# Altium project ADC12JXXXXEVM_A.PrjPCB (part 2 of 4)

## Sheet ADC12JXXXXEVM_A_3_TRF3765.SchDoc: TRF3765
size 431 x 279 mm; Date: Not shown in title block; ApprovedBy: Not shown in title block; CheckedBy: Not shown in title block; Author: Not shown in title block; CompanyName: Not shown in title block; DrawnBy: Not shown in title block; Engineer: Not shown in title block; Organization: Not shown in title block; Address1: Not shown in title block; Address2: Not shown in title block; Address3: Not shown in title block; Address4: Not shown in title block; DocumentNumber: 3; Revision: Use project parameter SCH_Rev; SheetNumber: 3; SheetTotal: 7; PageSetup: Record=PageOptions|CenterHorizontal=True|CenterVertical=True|PrintScale=0.49|XCorrection=1.00|YCorrection=1.00|PrintKind=0|BorderSize=5000000|LeftOffset=0|BottomOffset=0|Orientation=2|PaperLength=1000|PaperWidth=1000|Scale=100|PaperSource=15|PrintQuality=600|MediaType=1|DitherType=10|PaperKind=11x17|PrintScaleMode=1

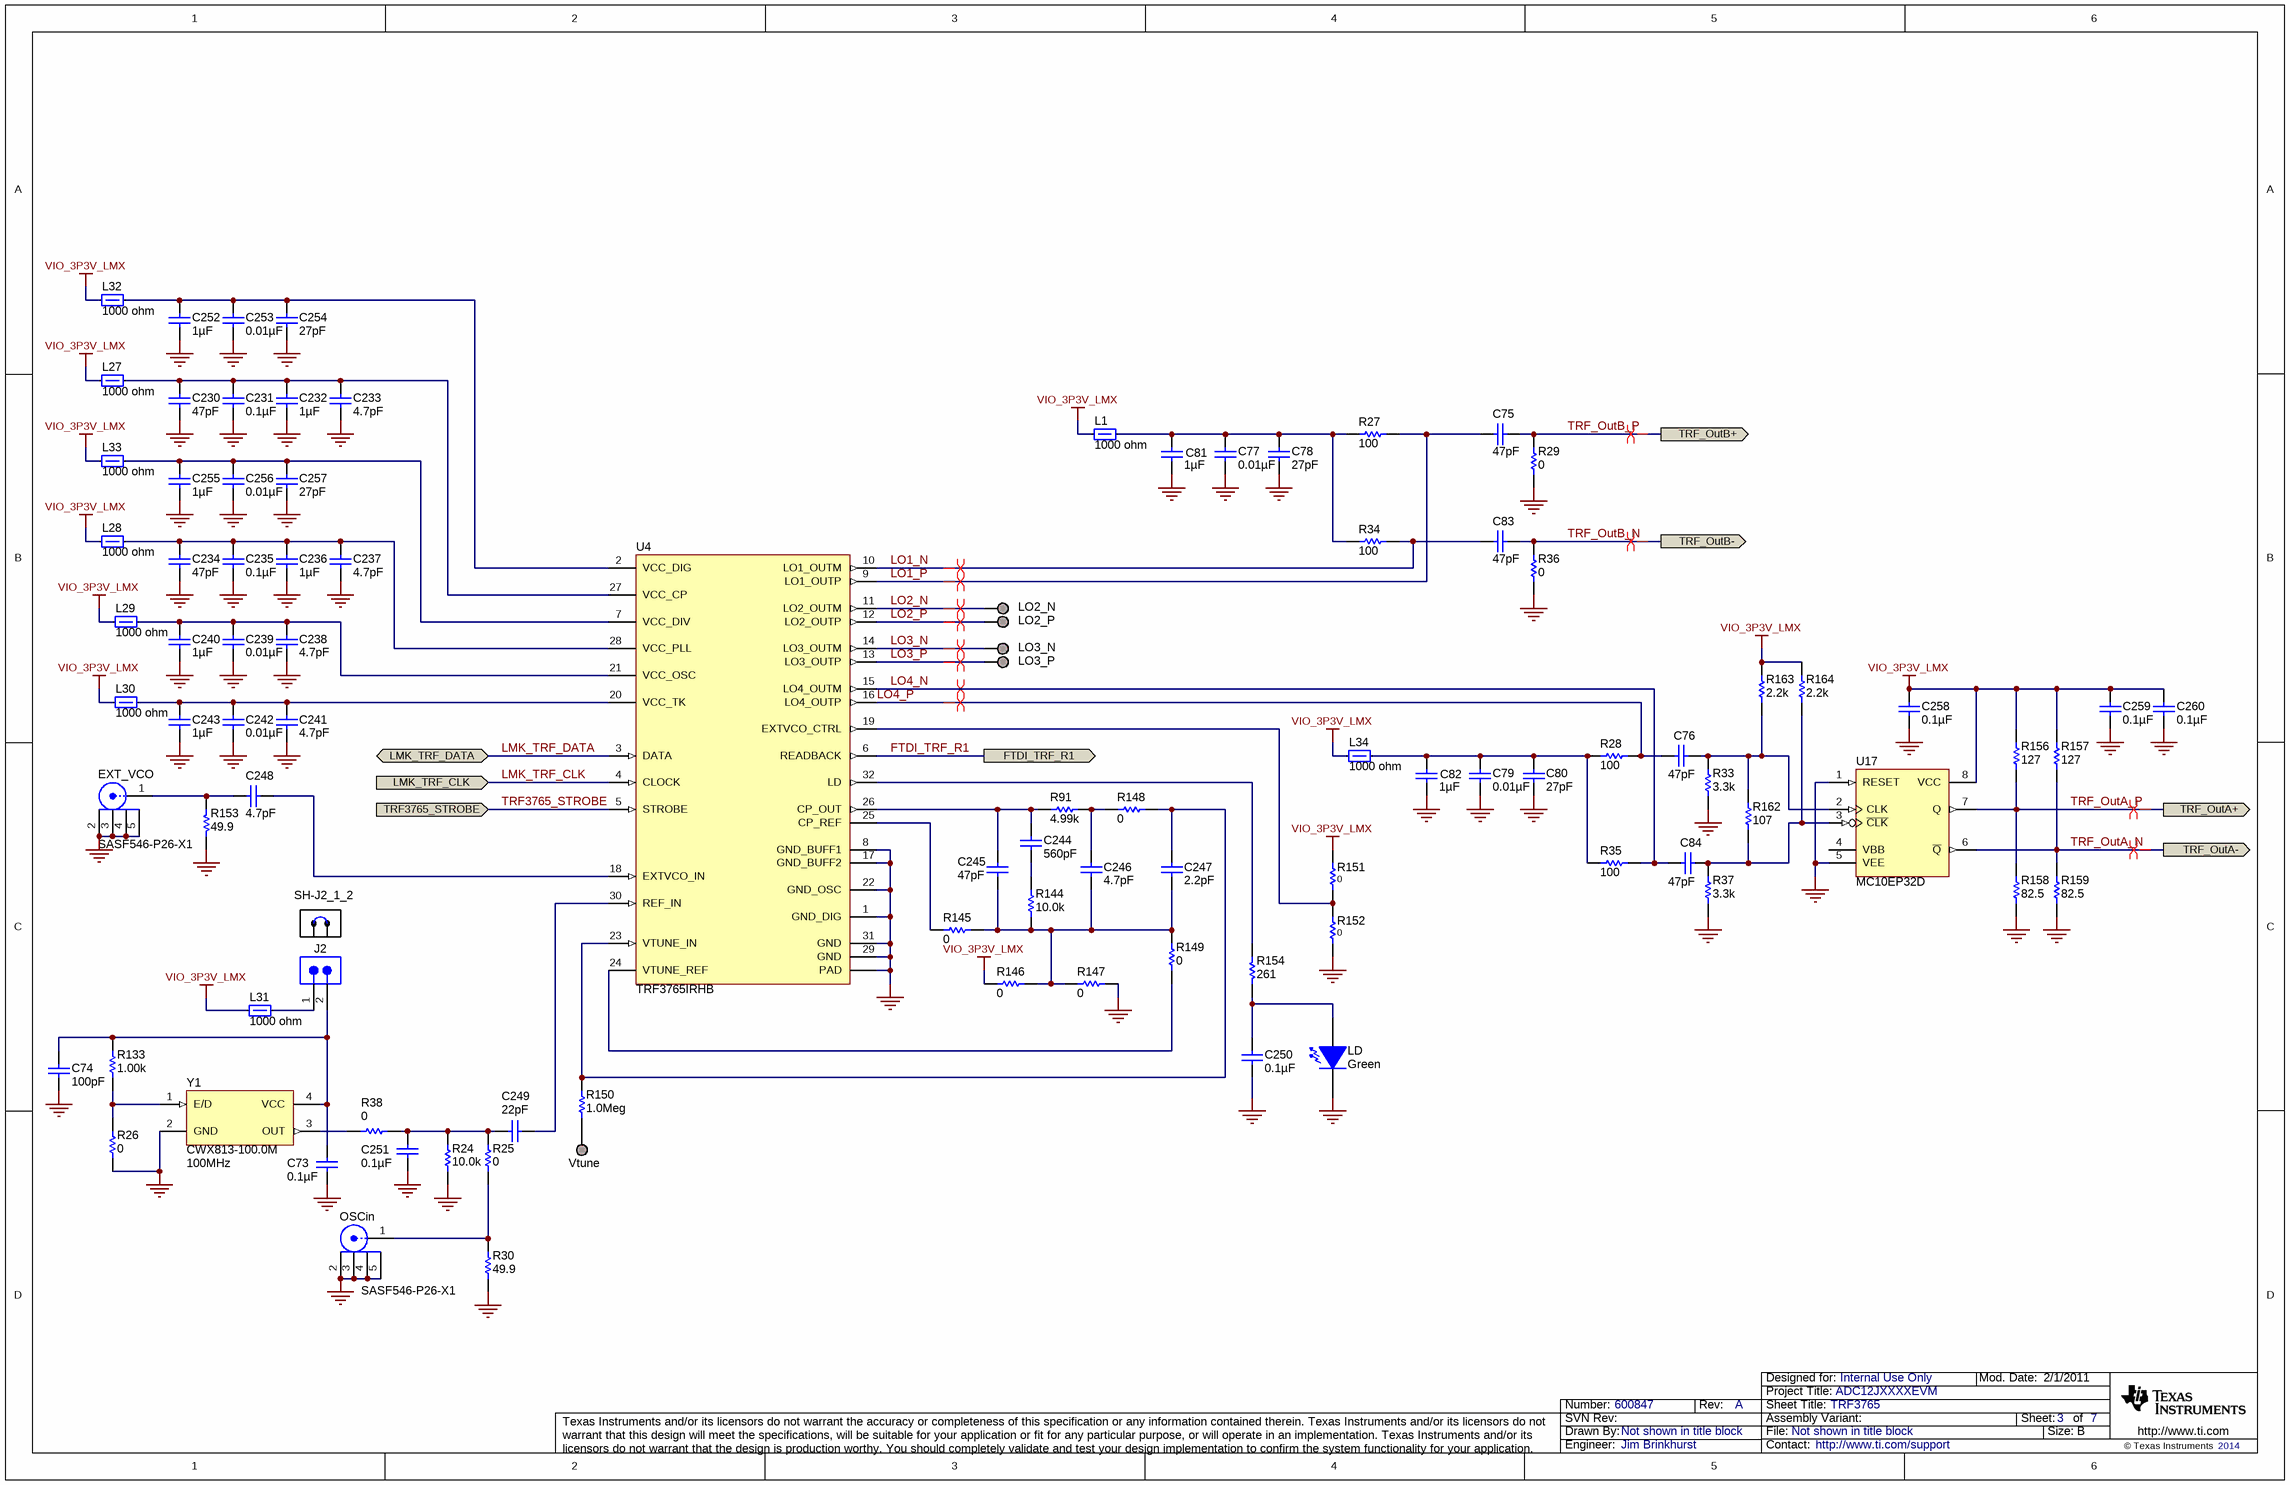
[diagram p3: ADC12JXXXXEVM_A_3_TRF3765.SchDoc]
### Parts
C73  ValueDisplayed: 0.1µF  [0402L]  (hidden comment: C1005X5R1A104K)
C74  ValueDisplayed: 100pF  [0402L]  (hidden comment: GRM1555C1E101JA01D)
C75  ValueDisplayed: 47pF  [0402L]  (hidden comment: GRM1555C1H470JA01D)
C76  ValueDisplayed: 47pF  [0402L]  (hidden comment: GRM1555C1H470JA01D)
C77  ValueDisplayed: 0.01µF  [0402L]  (hidden comment: GRM155R71E103KA01D)
C78  ValueDisplayed: 27pF  [0402L]  (hidden comment: GRM1555C1H270JA01D)
C79  ValueDisplayed: 0.01µF  [0402L]  (hidden comment: GRM155R71E103KA01D)
C80  ValueDisplayed: 27pF  [0402L]  (hidden comment: GRM1555C1H270JA01D)
C81  ValueDisplayed: 1µF  [0402L]  (hidden comment: C1005X5R0J105M)
C82  ValueDisplayed: 1µF  [0402L]  (hidden comment: C1005X5R0J105M)
C83  ValueDisplayed: 47pF  [0402L]  (hidden comment: GRM1555C1H470JA01D)
C84  ValueDisplayed: 47pF  [0402L]  (hidden comment: GRM1555C1H470JA01D)
C230  ValueDisplayed: 47pF  [0603L]  (hidden comment: GRM1885C1H470JA01D)
C231  ValueDisplayed: 0.1µF  [0402L]  (hidden comment: C1005X5R1A104K)
C232  ValueDisplayed: 1µF  [0402L]  (hidden comment: C1005X5R0J105M)
C233  ValueDisplayed: 4.7pF  [0402L]  (hidden comment: GRM1555C1H4R7CA01D)
C234  ValueDisplayed: 47pF  [0603L]  (hidden comment: GRM1885C1H470JA01D)
C235  ValueDisplayed: 0.1µF  [0402L]  (hidden comment: C1005X5R1A104K)
C236  ValueDisplayed: 1µF  [0402L]  (hidden comment: C1005X5R0J105M)
C237  ValueDisplayed: 4.7pF  [0402L]  (hidden comment: GRM1555C1H4R7CA01D)
C238  ValueDisplayed: 4.7pF  [0402L]  (hidden comment: GRM1555C1H4R7CA01D)
C239  ValueDisplayed: 0.01µF  [0402L]  (hidden comment: GRM155R71E103KA01D)
C240  ValueDisplayed: 1µF  [0402L]  (hidden comment: C1005X5R0J105M)
C241  ValueDisplayed: 4.7pF  [0402L]  (hidden comment: GRM1555C1H4R7CA01D)
C242  ValueDisplayed: 0.01µF  [0402L]  (hidden comment: GRM155R71E103KA01D)
C243  ValueDisplayed: 1µF  [0402L]  (hidden comment: C1005X5R0J105M)
C244  ValueDisplayed: 560pF  [0402L]  (hidden comment: GRM1555C1H561JA01D)
C245  ValueDisplayed: 47pF  [0402L]  (hidden comment: GRM1555C1H470JA01D)
C246  ValueDisplayed: 4.7pF  [0402L]  (hidden comment: GRM1555C1H4R7CA01D)
C247  ValueDisplayed: 2.2pF  [0402L]  (hidden comment: GRM1555C1H2R2CA01D)
C248  ValueDisplayed: 4.7pF  [0402L]  (hidden comment: GRM1555C1H4R7CA01D)
C249  ValueDisplayed: 22pF  [0402L]  (hidden comment: GRM1555C1H220JA01D)
C250  ValueDisplayed: 0.1µF  [0402L]  (hidden comment: C1005X5R1A104K)
C251  ValueDisplayed: 0.1µF  [0402L]  (hidden comment: C1005X5R1A104K)
C252  ValueDisplayed: 1µF  [0402L]  (hidden comment: C1005X5R0J105M)
C253  ValueDisplayed: 0.01µF  [0402L]  (hidden comment: GRM155R71E103KA01D)
C254  ValueDisplayed: 27pF  [0402L]  (hidden comment: GRM1555C1H270JA01D)
C255  ValueDisplayed: 1µF  [0402L]  (hidden comment: C1005X5R0J105M)
C256  ValueDisplayed: 0.01µF  [0402L]  (hidden comment: GRM155R71E103KA01D)
C257  ValueDisplayed: 27pF  [0402L]  (hidden comment: GRM1555C1H270JA01D)
C258  ValueDisplayed: 0.1µF  [0402L]  (hidden comment: C1005X5R1A104K)
C259  ValueDisplayed: 0.1µF  [0402L]  (hidden comment: C1005X5R1A104K)
C260  ValueDisplayed: 0.1µF  [0402L]  (hidden comment: C1005X5R1A104K)
EXT_VCO  SASF546-P26-X1  [CONN_LTI_SASF546-P26-X1]
J2  TSW-102-07-G-S  [TSW-102-07-G-S]  (value not drawn)
L1  value 1000 ohm  [0402L]  (hidden comment: BLM15HG102SN1D)
L27  value 1000 ohm  [0402L]  (hidden comment: BLM15HG102SN1D)
L28  value 1000 ohm  [0402L]  (hidden comment: BLM15HG102SN1D)
L29  value 1000 ohm  [0402L]  (hidden comment: BLM15HG102SN1D)
L30  value 1000 ohm  [0402L]  (hidden comment: BLM15HG102SN1D)
L31  value 1000 ohm  [0402L]  (hidden comment: BLM15HG102SN1D)
L32  value 1000 ohm  [0402L]  (hidden comment: BLM15HG102SN1D)
L33  value 1000 ohm  [0402L]  (hidden comment: BLM15HG102SN1D)
L34  value 1000 ohm  [0402L]  (hidden comment: BLM15HG102SN1D)
LD  value Green  [LED_LTST-C190]  (hidden comment: LTST-C190GKT)
LO2_N  TESTPOINT  [TESTPOINT]  (value not drawn)  (no BOM)
LO2_P  TESTPOINT  [TESTPOINT]  (value not drawn)  (no BOM)
LO3_N  TESTPOINT  [TESTPOINT]  (value not drawn)  (no BOM)
LO3_P  TESTPOINT  [TESTPOINT]  (value not drawn)  (no BOM)
OSCin  SASF546-P26-X1  [CONN_LTI_SASF546-P26-X1]
R24  value 10.0k  [0402L]  (hidden comment: CRCW040210K0FKED)
R25  value 0  [0402L]  (hidden comment: ERJ-2GE0R00X)
R26  value 0  [0402L]  (hidden comment: ERJ-2GE0R00X)
R27  value 100  [0402L]  (hidden comment: CRCW0402100RFKED)
R28  value 100  [0402L]  (hidden comment: CRCW0402100RFKED)
R29  value 0  [0402L]  (hidden comment: ERJ-2GE0R00X)
R30  value 49.9  [0402L]  (hidden comment: CRCW040249R9FKED)
R33  value 3.3k  [0402L]  (hidden comment: CRCW04023K30JNED)
R34  value 100  [0402L]  (hidden comment: CRCW0402100RFKED)
R35  value 100  [0402L]  (hidden comment: CRCW0402100RFKED)
R36  value 0  [0402L]  (hidden comment: ERJ-2GE0R00X)
R37  value 3.3k  [0402L]  (hidden comment: CRCW04023K30JNED)
R38  value 0  [0402L]  (hidden comment: ERJ-2GE0R00X)
R91  value 4.99k  [0402L]  (hidden comment: CRCW04024K99FKED)
R133  value 1.00k  [0402L]  (hidden comment: CRCW04021K00FKED)
R144  value 10.0k  [0402L]  (hidden comment: CRCW040210K0FKED)
R145  value 0  [0402L]  (hidden comment: ERJ-2GE0R00X)
R146  value 0  [0402L]  (hidden comment: ERJ-2GE0R00X)
R147  value 0  [0402L]  (hidden comment: ERJ-2GE0R00X)
R148  value 0  [0402L]  (hidden comment: ERJ-2GE0R00X)
R149  value 0  [0402L]  (hidden comment: ERJ-2GE0R00X)
R150  value 1.0Meg  [0402L]  (hidden comment: CRCW04021M00JNED)
R151  value 0  [0603L]  (hidden comment: CRCW06030000Z0EA)
R152  value 0  [0603L]  (hidden comment: CRCW06030000Z0EA)
R153  value 49.9  [0402L]  (hidden comment: CRCW040249R9FKED)
R154  value 261  [0402L]  (hidden comment: CRCW040215K0JNED)
R156  value 127  [0402L]  (hidden comment: CRCW0402127RFKED)
R157  value 127  [0402L]  (hidden comment: CRCW0402127RFKED)
R158  value 82.5  [0402L]  (hidden comment: CRCW040282R5FKED)
R159  value 82.5  [0402L]  (hidden comment: CRCW040282R5FKED)
R162  value 107  [0402L]  (hidden comment: CRCW0402107RFKED)
R163  value 2.2k  [0402L]  (hidden comment: CRCW04022K20JNED)
R164  value 2.2k  [0402L]  (hidden comment: CRCW04022K20JNED)
SH-J2_1_2  SNT-100-BK-G  [SNT-100-BK-G]  (value not drawn)
U4  TRF3765IRHB  [RHB0032E]
U17  MC10EP32D  [751-06_N]
Vtune  TESTPOINT  [TESTPOINT]  (value not drawn)  (no BOM)
Y1  CWX813-100.0M  Frequency: 100MHz  [OSC_CWX]

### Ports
FTDI_TRF_R1, LMK_TRF_CLK, LMK_TRF_DATA (bidir), TRF3765_STROBE, TRF_OutA+ (out), TRF_OutA- (out), TRF_OutB+, TRF_OutB-

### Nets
GND: C73.1 C74.1 C77.2 C78.2 C79.2 C80.2 C81.2 C82.2 C230.2 C231.1 C232.2 C233.2 C234.2 C235.1 C236.2 C237.2 C238.2 C239.2 C240.2 C241.2 C242.2 C243.2 C250.1 C251.1 C252.2 C253.2 C254.2 C255.2 C256.2 C257.2 C258.1 C259.1 C260.1 EXT_VCO.2 EXT_VCO.3 EXT_VCO.4 EXT_VCO.5 LD.2(K) OSCin.2 OSCin.3 OSCin.4 OSCin.5 R24.1 R26.1 R29.1 R30.1 R33.1 R36.1 R37.1 R147.2 R152.2 R153.1 R158.1 R159.1 U4.1(GND_DIG) U4.8(GND_BUFF1) U4.17(GND_BUFF2) U4.22(GND_OSC) U4.29(GND) U4.31(GND) U4.33(PAD) U17.1(RESET) U17.5(VEE) Y1.2(GND)
VIO_3P3V_LMX: C258.2 C259.2 C260.2 L1.1 L27.1 L28.1 L29.1 L30.1 L31.1 L32.1 L33.1 L34.1 R146.1 R151.1 R156.2 R157.2 R163.2 R164.2 U17.8(VCC)
FTDI_TRF_R1: U4.6(READBACK) ; port FTDI_TRF_R1
LMK_TRF_CLK: U4.4(CLOCK) ; port LMK_TRF_CLK
LMK_TRF_DATA: U4.3(DATA) ; port LMK_TRF_DATA
LO1_N: C83.1 R34.2 U4.10(LO1_OUTM)
LO1_P: C75.1 R27.2 U4.9(LO1_OUTP)
LO2_N: LO2_N.1 U4.11(LO2_OUTM)
LO2_P: LO2_P.1 U4.12(LO2_OUTP)
LO3_N: LO3_N.1 U4.14(LO3_OUTM)
LO3_P: LO3_P.1 U4.13(LO3_OUTP)
LO4_N: C84.1 R35.2 U4.15(LO4_OUTM)
LO4_P: C76.1 R28.2 U4.16(LO4_OUTP)
TRF3765_STROBE: U4.5(STROBE) ; port TRF3765_STROBE
TRF_OutA_N: R157.1 R159.2 U17.6(~{Q}) ; port TRF_OutA-
TRF_OutA_P: R156.1 R158.2 U17.7(Q) ; port TRF_OutA+
TRF_OutB_N: C83.2 R36.2 ; port TRF_OutB-
TRF_OutB_P: C75.2 R29.2 ; port TRF_OutB+
NetC73_2: C73.2 C74.2 J2.2 R133.2 Y1.4(VCC)
NetC76_2: C76.2 R33.2 R162.2 R163.1 U17.2(CLK)
NetC77_1: C77.1 C78.1 C81.1 L1.2 R27.1 R34.1
NetC79_1: C79.1 C80.1 C82.1 L34.2 R28.1 R35.1
NetC84_2: C84.2 R37.2 R162.1 R164.1 U17.3(~{CLK})
NetC230_1: C230.1 C231.2 C232.1 C233.1 L27.2 U4.27(VCC_CP)
NetC234_1: C234.1 C235.2 C236.1 C237.1 L28.2 U4.28(VCC_PLL)
NetC238_1: C238.1 C239.1 C240.1 L29.2 U4.21(VCC_OSC)
NetC241_1: C241.1 C242.1 C243.1 L30.2 U4.20(VCC_TK)
NetC244_1: C244.1 C245.1 R91.1 U4.26(CP_OUT)
NetC244_2: C244.2 R144.2
NetC245_2: C245.2 C246.2 C247.2 R144.1 R145.2 R146.2 R147.1 R149.1
NetC246_1: C246.1 R91.2 R148.1
NetC247_1: C247.1 R148.2 R150.1 U4.23(VTUNE_IN)
NetC248_1: C248.1 U4.18(EXTVCO_IN)
NetC248_2: C248.2 EXT_VCO.1 R153.2
NetC249_1: C249.1 U4.30(REF_IN)
NetC249_2: C249.2 C251.2 R24.2 R25.2 R38.1
NetC250_2: C250.2 LD.1(A) R154.1
NetC252_1: C252.1 C253.1 C254.1 L32.2 U4.2(VCC_DIG)
NetC255_1: C255.1 C256.1 C257.1 L33.2 U4.7(VCC_DIV)
NetJ2_1: J2.1 L31.2
NetOSCin_1: OSCin.1 R25.1 R30.2
NetR26_2: R26.2 R133.1 Y1.1(E/D)
NetR38_2: R38.2 Y1.3(OUT)
NetR145_1: R145.1 U4.25(CP_REF)
NetR149_2: R149.2 U4.24(VTUNE_REF)
NetR150_2: R150.2 Vtune.1
NetR151_2: R151.2 R152.1 U4.19(EXTVCO_CTRL)
NetR154_2: R154.2 U4.32(LD)

Not connected (* = marked no-connect by the designer): U17 4(VBB)

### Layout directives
differential pair: LO1_N, LO1_P, LO2_N, LO2_P, LO3_N, LO3_P, LO4_N, LO4_P, TRF_OutA_N, TRF_OutA_P, TRF_OutB_N, TRF_OutB_P

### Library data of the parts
C73 C231 C235 C250 C251 C258-C260 = C1005X5R1A104K: CAP, CERM, 0.1uF, 10V, +/-10%, X5R, 0402; Manufacturer: TDK; Polarized: N; CompType: Capacitor; U/M: EA; Cap_F: 0.0000001; Tolerance_%: 10; ESR_Ohm: 0.0186; Value1: 0.0186 ohm; TaMin_C: -55; TaMax_C: 85; Cap_Case: 0402
C74 = GRM1555C1E101JA01D: CAP, CERM, 100pF, 25V, +/-5%, C0G/NP0, 0402; Manufacturer: MuRata; Cap_Case: 0402; Polarized: N; TaMax_C: 125; TaMin_C: -55; Tolerance_%: 5; VDC_V: 25; Cap_F: 0.0000000001; CompType: Capacitor; U/M: EA
C75 C76 C83 C84 C245 = GRM1555C1H470JA01D: CAP, CERM, 47pF, 50V, +/-5%, C0G/NP0, 0402; Manufacturer: MuRata; Polarized: N; CompType: Capacitor; U/M: EA; Cap_F: 0.000000000047; Tolerance_%: 5; Value1: Unknown; VDC_V: 50; TaMin_C: -55; TaMax_C: 125; Cap_Case: 0402
C77 C79 C239 C242 C253 C256 = GRM155R71E103KA01D: CAP, CERM, 0.01uF, 25V, +/-10%, X7R, 0402; Manufacturer: MuRata; Polarized: N; CompType: Capacitor; U/M: EA; Cap_F: 0.00000001; Tolerance_%: 10; Value1: Unknown; VDC_V: 25; TaMin_C: -55; TaMax_C: 125; Cap_Case: 0402
C78 C80 C254 C257 = GRM1555C1H270JA01D: CAP, CERM, 27pF, 50V, +/-5%, C0G/NP0, 0402; Manufacturer: MuRata; Polarized: N; CompType: Capacitor; U/M: EA; Cap_F: 0.000000000027; Tolerance_%: 5; Value1: Unknown; VDC_V: 50; TaMin_C: -55; TaMax_C: 125; Cap_Case: 0402
C81 C82 C232 C236 C240 C243 C252 C255 = C1005X5R0J105M: CAP, CERM, 1uF, 6.3V, +/-20%, X5R, 0402; Manufacturer: TDK; Polarized: N; CompType: Capacitor; U/M: EA; Cap_F: 0.000001; Tolerance_%: 20; ESR_Ohm: 0.0079; Value1: 0.0079 ohm; VDC_V: 6.3; TaMin_C: -55; TaMax_C: 85; Cap_Case: 0402
C230 C234 = GRM1885C1H470JA01D: CAP, CERM, 47pF, 50V, +/-5%, C0G/NP0, 0603; Manufacturer: MuRata; Polarized: N; CompType: Capacitor; U/M: EA; Cap_F: 0.000000000047; Tolerance_%: 5; Value1: Unknown; VDC_V: 50; TaMin_C: -55; TaMax_C: 125; Cap_Case: 0603
C233 C237 C238 C241 C246 C248 = GRM1555C1H4R7CA01D: CAP, CERM, 4.7pF, 50V, +/-5%, C0G/NP0, 0402; Manufacturer: MuRata; Polarized: N; CompType: Capacitor; U/M: EA; Cap_F: 0.0000000000047; Tolerance_%: 5; Value1: Unknown; VDC_V: 50; TaMin_C: -55; TaMax_C: 125; Cap_Case: 0402
C244 = GRM1555C1H561JA01D: CAP, CERM, 560pF, 50V, +/-5%, C0G/NP0, 0402; Manufacturer: MuRata; Polarized: N; CompType: Capacitor; U/M: EA; Cap_F: 0.00000000056; Tolerance_%: 5; Value1: Unknown; VDC_V: 50; TaMin_C: -55; TaMax_C: 125; Cap_Case: 0402
C247 = GRM1555C1H2R2CA01D: CAP, CERM, 2.2pF, 50V, +/-5%, C0G/NP0, 0402; Manufacturer: MuRata; Polarized: N; CompType: Capacitor; U/M: EA; Cap_F: 0.0000000000022; Tolerance_%: 5; Value1: Unknown; VDC_V: 50; TaMin_C: -55; TaMax_C: 125; Cap_Case: 0402
C249 = GRM1555C1H220JA01D: CAP, CERM, 22pF, 50V, +/-5%, C0G/NP0, 0402; Manufacturer: MuRata; Polarized: N; CompType: Capacitor; U/M: EA; Cap_F: 0.000000000022; Tolerance_%: 5; Value1: Unknown; VDC_V: 50; TaMin_C: -55; TaMax_C: 125; Cap_Case: 0402
EXT_VCO OSCin = SASF546-P26-X1: Connector, SMA,Vertical, Thru hole w/SMT center pin; Manufacturer: Lighthorse Technologies; U/M: EA
J2 = TSW-102-07-G-S: Header, TH, 100mil, 2x1, Gold plated, 230 mil above insulator; Manufacturer: Samtec, Inc.; U/M: EA
L1 L27-L34 = BLM15HG102SN1D: 0.25A Ferrite Bead, 1000 ohm @ 100MHz, SMD; Manufacturer: MuRata; Imax_A: 0.25; Irms: 0.25A @ C rise; Isat: 0.25A @ % inductance drop; DCR_ohm: 1.1; Value1: 1.1 ohm; ZTyp@100MHz_Ohm: 1000; U/M: EA
LD = LTST-C190GKT: LED, Green, SMD; Manufacturer: Lite-On; Vf_V: 2.1; Value2: 2.1V; Io_A: 0.02; Power_TotalModule: 0.1; Value1: 0.1W; U/M: EA
LO2_N LO2_P LO3_N LO3_P Vtune = TESTPOINT: TEST POINT.  No entry in BOM.
R24 R144 = CRCW040210K0FKED: RES, 10.0k ohm, 1%, 0.063W, 0402; Manufacturer: Vishay-Dale; CompType: Resistor; Res_ohm: 10000; Value_Code: 10k0; Tolerance_%: 1; Power_W: 0.063; VDC_V: 50; TempCo: 100 ppm/C; EIA_Code: E96; U/M: EA
R25 R26 R29 R36 R38 R145-R149 = ERJ-2GE0R00X: RES, 0 ohm, 5%, 0.063W, 0402; Manufacturer: Panasonic; CompType: Resistor; Value_Code: 0000; Tolerance_%: 5; Power_W: 0.063; VDC_V: 50; TempCo: 600 ppm/C; EIA_Code: E24; U/M: EA
R27 R28 R34 R35 = CRCW0402100RFKED: RES, 100 ohm, 1%, 0.063W, 0402; Manufacturer: Vishay-Dale; CompType: Resistor; Value_Code: 100R; Tolerance_%: 1; Power_W: 0.063; VDC_V: 50; TempCo: 100 ppm/C; EIA_Code: E96; U/M: EA
R30 R153 = CRCW040249R9FKED: RES, 49.9 ohm, 1%, 0.063W, 0402; Manufacturer: Vishay-Dale; CompType: Resistor; Value_Code: 49R9; Tolerance_%: 1; Power_W: 0.063; VDC_V: 50; TempCo: 100 ppm/C; EIA_Code: E96; U/M: EA
R33 R37 = CRCW04023K30JNED: RES, 3.3k ohm, 5%, 0.063W, 0402; Manufacturer: Vishay-Dale; CompType: Resistor; Res_ohm: 3300; Value_Code: 3k30; Tolerance_%: 5; Power_W: 0.063; VDC_V: 50; TempCo: 200 ppm/C; EIA_Code: E24; U/M: EA
R91 = CRCW04024K99FKED: RES, 4.99k ohm, 1%, 0.063W, 0402; Manufacturer: Vishay-Dale; CompType: Resistor; Res_ohm: 4990; Value_Code: 4k99; Tolerance_%: 1; Power_W: 0.063; VDC_V: 50; TempCo: 100 ppm/C; EIA_Code: E96; U/M: EA
R133 = CRCW04021K00FKED: RES, 1.00k ohm, 1%, 0.063W, 0402; Manufacturer: Vishay-Dale; CompType: Resistor; Res_ohm: 1000; Value_Code: 1k00; Tolerance_%: 1; Power_W: 0.063; VDC_V: 50; TempCo: 100 ppm/C; EIA_Code: E96; U/M: EA
R150 = CRCW04021M00JNED: RES, 1.0Meg ohm, 5%, 0.063W, 0402; Manufacturer: Vishay-Dale; CompType: Resistor; Res_ohm: 1000000; Value_Code: 1M00; Tolerance_%: 5; Power_W: 0.063; VDC_V: 50; TempCo: 200 ppm/C; EIA_Code: E24; U/M: EA
R151 R152 = CRCW06030000Z0EA: RES, 0 ohm, 5%, 0.1W, 0603; Manufacturer: Vishay-Dale; CompType: Resistor; Tolerance_%: 5; VDC_V: 75; Power_W: 0.1; U/M: EA; Value_Code: 0000; EIA_Code: E24
R154 = CRCW040215K0JNED: RES, 15k ohm, 5%, 0.063W, 0402; Manufacturer: Vishay-Dale; CompType: Resistor; Res_ohm: 15000; Value_Code: 15k0; Tolerance_%: 5; Power_W: 0.063; VDC_V: 50; TempCo: 200 ppm/C; EIA_Code: E24; U/M: EA
R156 R157 = CRCW0402127RFKED: RES, 127 ohm, 1%, 0.063W, 0402; Manufacturer: Vishay-Dale; CompType: Resistor; Value_Code: 127R; Tolerance_%: 1; Power_W: 0.063; VDC_V: 50; TempCo: 100 ppm/C; EIA_Code: E96; U/M: EA
R158 R159 = CRCW040282R5FKED: RES, 82.5 ohm, 1%, 0.063W, 0402; Manufacturer: Vishay-Dale; CompType: Resistor; Value_Code: 82R5; Tolerance_%: 1; Power_W: 0.063; VDC_V: 50; TempCo: 100 ppm/C; EIA_Code: E96; U/M: EA
R162 = CRCW0402107RFKED: RES, 107 ohm, 1%, 0.063W, 0402; Manufacturer: Vishay-Dale; CompType: Resistor; Value_Code: 107R; Tolerance_%: 1; Power_W: 0.063; VDC_V: 50; TempCo: 100 ppm/C; EIA_Code: E96; U/M: EA
R163 R164 = CRCW04022K20JNED: RES, 2.2k ohm, 5%, 0.063W, 0402; Manufacturer: Vishay-Dale; CompType: Resistor; Res_ohm: 2200; Value_Code: 2k20; Tolerance_%: 5; Power_W: 0.063; VDC_V: 50; TempCo: 200 ppm/C; EIA_Code: E24; U/M: EA
SH-J2_1_2 = SNT-100-BK-G: Shunt, 100mil, Gold plated, Black; Manufacturer: Samtec, Inc.; Alternate Manufacturer: 3M; Alternate PartNumber: 969102-0000-DA; Value: 1x2; Note: You can "mate" this to a header by matching the designator.  i.e. use SH-J3 for header J3
U4 = TRF3765IRHB: Integer-N/Fractional-N PLL with Integrated VCO, RHB0032E; Alternate Manufacturer: None; Manufacturer: Texas Instruments; SymbolCreator: x0208326; CompType: IC; U/M: EA
U17 = MC10EP32D: Divide-by-2 Divider; Manufacturer: ON Semiconductor; PartNumber: MC10EP32DG
Y1 = CWX813-100.0M: OSC 100.0000MHZ 3.3V +-25PPM SMD; Manufacturer: Connor-Winfield; SymbolCreator: a0411947; CompType: Crystal; U/M: EA; TaMin_C: -20; TaMax_C: 70; Frequency Stability: ±25ppm

## Sheet ADC12JXXXXEVM_A_4_LMK04828.SchDoc
size 431 x 279 mm; Date: Not shown in title block; ApprovedBy: Not shown in title block; CheckedBy: Not shown in title block; Author: Not shown in title block; CompanyName: Not shown in title block; Engineer: Not shown in title block; Organization: Not shown in title block; Address1: Not shown in title block; Address2: Not shown in title block; Address3: Not shown in title block; Address4: Not shown in title block; DocumentNumber: 4; Revision: Use project parameter SCH_Rev; SheetNumber: 4; SheetTotal: 7; PageSetup: Record=PageOptions|CenterHorizontal=True|CenterVertical=True|PrintScale=0.47|XCorrection=1.00|YCorrection=1.00|PrintKind=0|BorderSize=5000000|LeftOffset=0|BottomOffset=0|Orientation=2|PaperLength=1000|PaperWidth=1000|Scale=100|PaperSource=7|PrintQuality=600|MediaType=1|DitherType=10|PaperKind=11" x 17"|PrintScaleMode=1

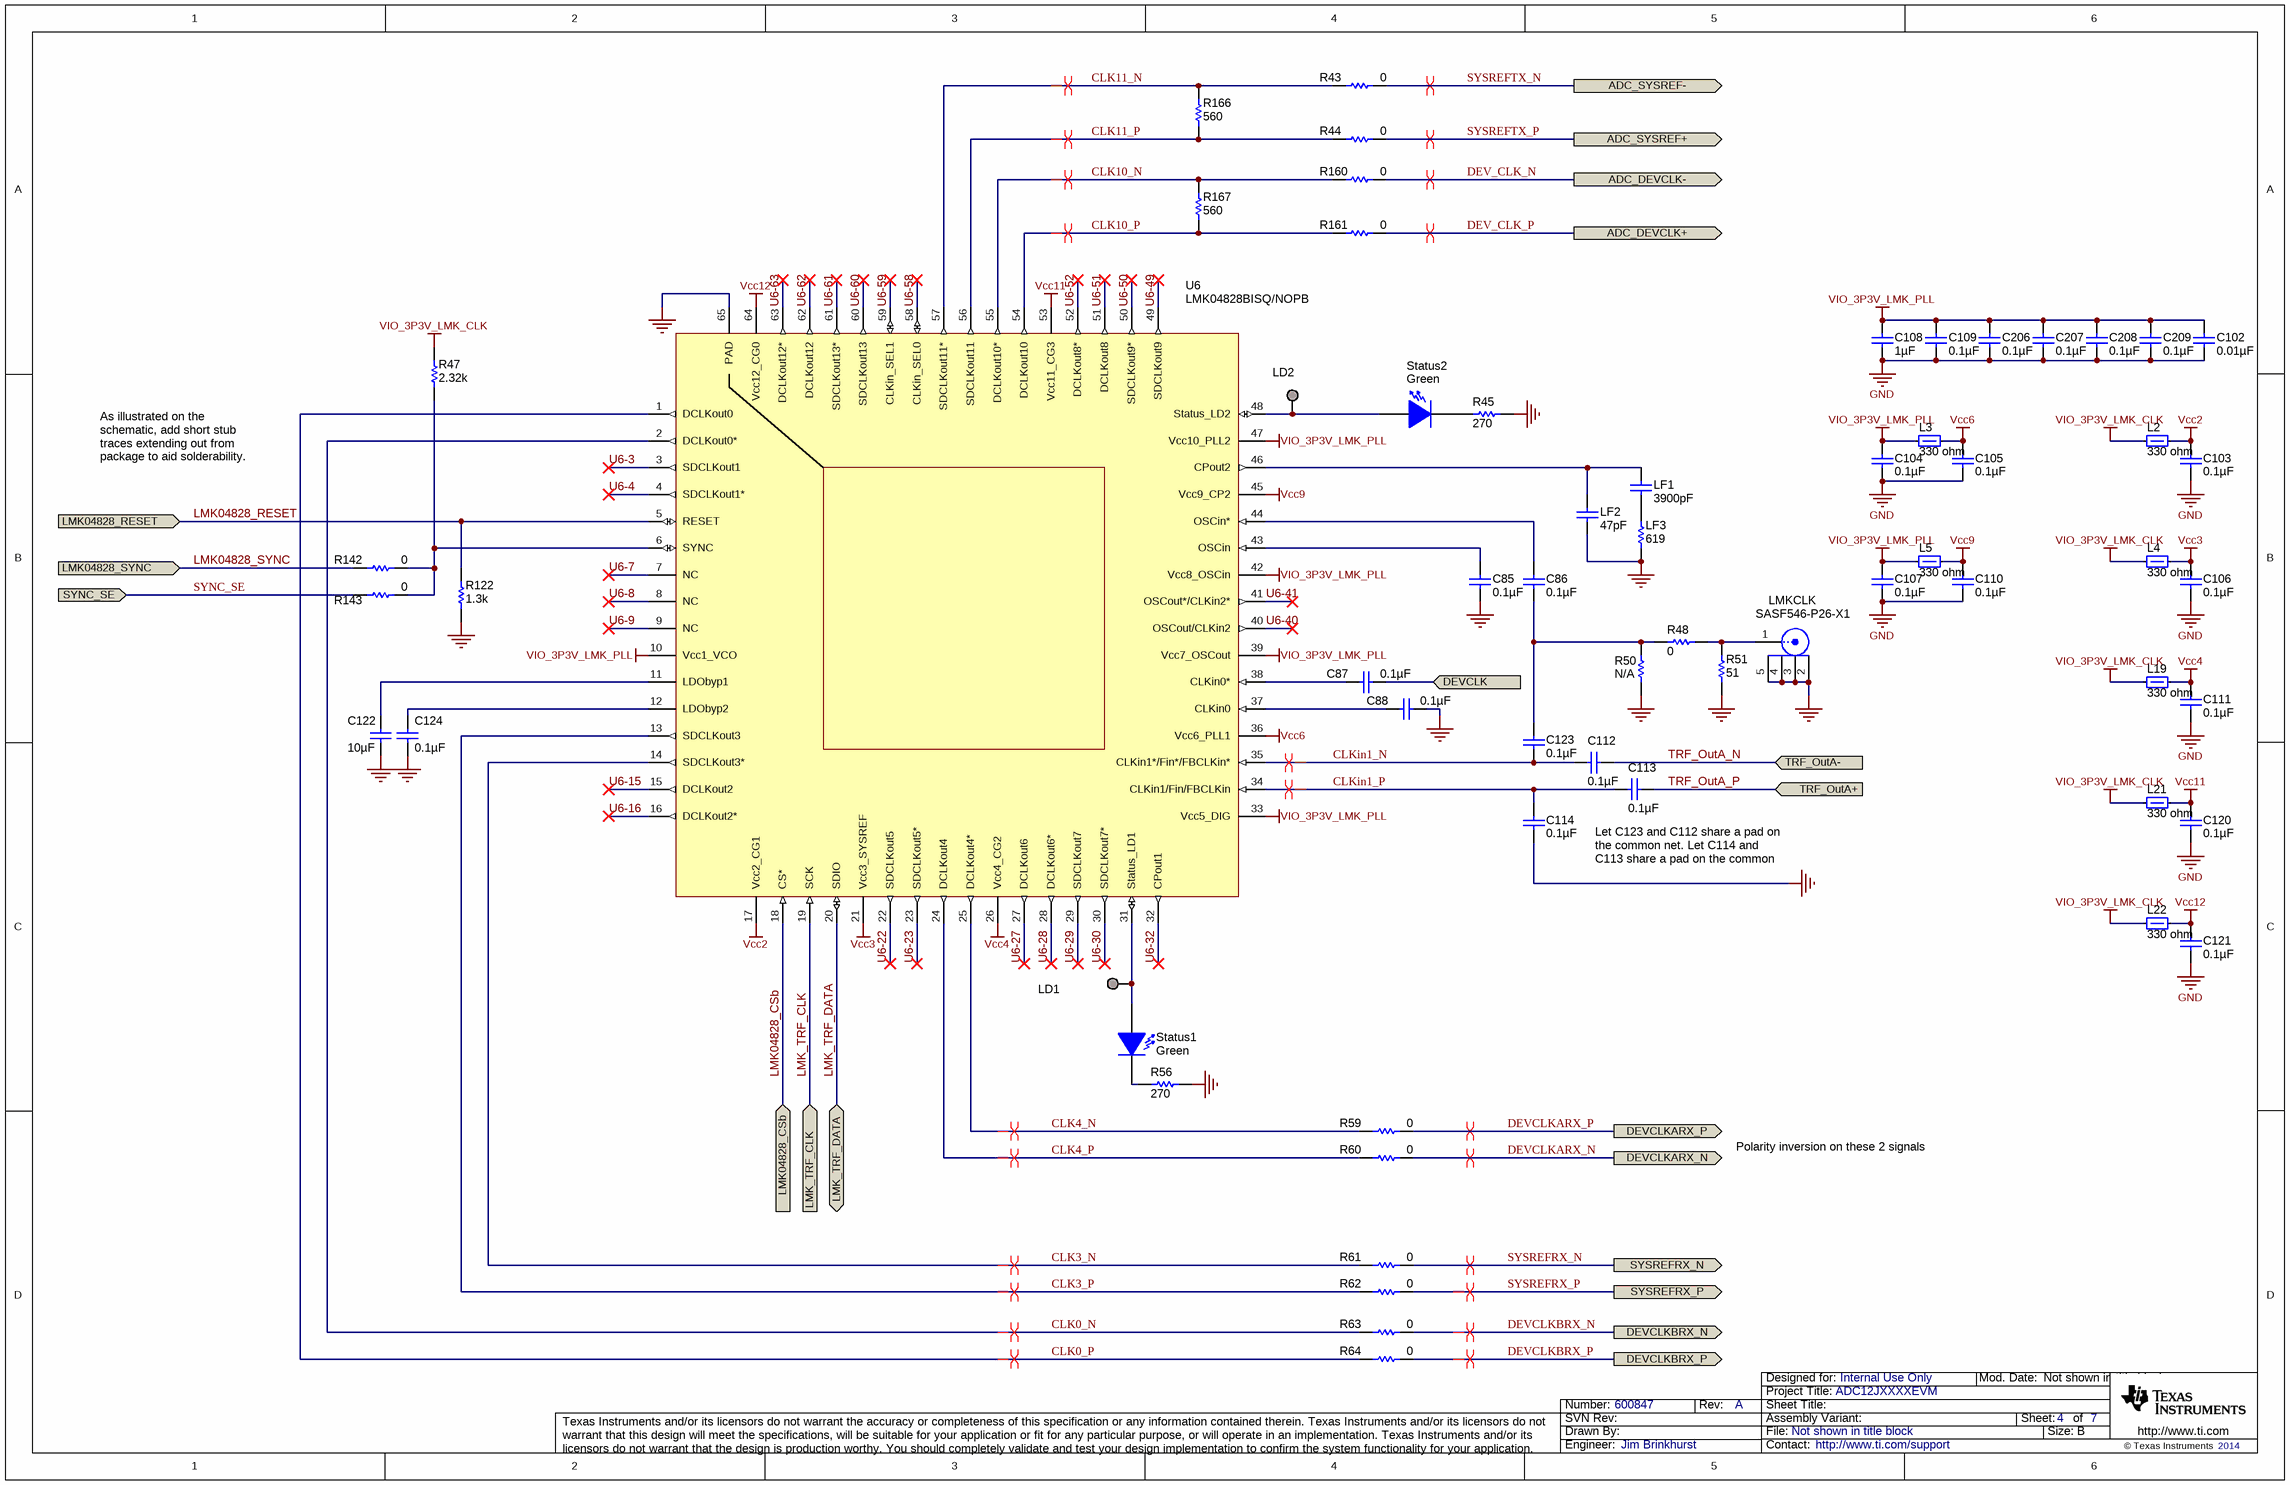
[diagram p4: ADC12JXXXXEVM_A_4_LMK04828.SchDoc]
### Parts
C85  ValueDisplayed: 0.1µF  [0402L]  (hidden comment: C1005X5R1A104K)
C86  ValueDisplayed: 0.1µF  [0402L]  (hidden comment: C1005X5R1A104K)
C87  ValueDisplayed: 0.1µF  [0402L]  (hidden comment: C1005X5R1A104K)
C88  ValueDisplayed: 0.1µF  [0402L]  (hidden comment: C1005X5R1A104K)
C102  ValueDisplayed: 0.01µF  [0402L]  (hidden comment: C1005X7R1C103K)
C103  ValueDisplayed: 0.1µF  [0402L]  (hidden comment: C1005X5R1A104K)
C104  ValueDisplayed: 0.1µF  [0402L]  (hidden comment: C1005X5R1A104K)
C105  ValueDisplayed: 0.1µF  [0402L]  (hidden comment: C1005X5R1A104K)
C106  ValueDisplayed: 0.1µF  [0402L]  (hidden comment: C1005X5R1A104K)
C107  ValueDisplayed: 0.1µF  [0402L]  (hidden comment: C1005X5R1A104K)
C108  ValueDisplayed: 1µF  [0603L]  (hidden comment: C1608X5R1C105K)
C109  ValueDisplayed: 0.1µF  [0402L]  (hidden comment: C1005X5R1A104K)
C110  ValueDisplayed: 0.1µF  [0402L]  (hidden comment: C1005X5R1A104K)
C111  ValueDisplayed: 0.1µF  [0402L]  (hidden comment: C1005X5R1A104K)
C112  ValueDisplayed: 0.1µF  [0402L]  (hidden comment: C1005X5R1A104K)
C113  ValueDisplayed: 0.1µF  [0402L]  (hidden comment: C1005X5R1A104K)
C114  ValueDisplayed: 0.1µF  [0402L]  (hidden comment: C1005X5R1A104K)
C120  ValueDisplayed: 0.1µF  [0402L]  (hidden comment: C1005X5R1A104K)
C121  ValueDisplayed: 0.1µF  [0402L]  (hidden comment: C1005X5R1A104K)
C122  ValueDisplayed: 10µF  [0805L]  (hidden comment: C0805C106K8PACTU)
C123  ValueDisplayed: 0.1µF  [0402L]  (hidden comment: C1005X5R1A104K)
C124  ValueDisplayed: 0.1µF  [0402L]  (hidden comment: C1005X5R1A104K)
C206  ValueDisplayed: 0.1µF  [0402L]  (hidden comment: C1005X5R1A104K)
C207  ValueDisplayed: 0.1µF  [0402L]  (hidden comment: C1005X5R1A104K)
C208  ValueDisplayed: 0.1µF  [0402L]  (hidden comment: C1005X5R1A104K)
C209  ValueDisplayed: 0.1µF  [0402L]  (hidden comment: C1005X5R1A104K)
L2  value 330 ohm  [0603]  (hidden comment: BLM18SG331TN1D)
L3  value 330 ohm  [0603]  (hidden comment: BLM18SG331TN1D)
L4  value 330 ohm  [0603]  (hidden comment: BLM18SG331TN1D)
L5  value 330 ohm  [0603]  (hidden comment: BLM18SG331TN1D)
L19  value 330 ohm  [0603]  (hidden comment: BLM18SG331TN1D)
L21  value 330 ohm  [0603]  (hidden comment: BLM18SG331TN1D)
L22  value 330 ohm  [0603]  (hidden comment: BLM18SG331TN1D)
LD1  TESTPOINT  [TESTPOINT]  (value not drawn)  (no BOM)
LD2  TESTPOINT  [TESTPOINT]  (value not drawn)  (no BOM)
LF1  ValueDisplayed: 3900pF  [0603L]  (hidden comment: C1608C0G1E392J)
LF2  ValueDisplayed: 47pF  [0603L]  (hidden comment: 06035A470JAT2A)
LF3  value 619  [0603L]  (hidden comment: RC0603FR-07619RL)
LMKCLK  SASF546-P26-X1  [CONN_LTI_SASF546-P26-X1]
R43  value 0  [0402L]  (hidden comment: CRCW04020000Z0ED)
R44  value 0  [0402L]  (hidden comment: CRCW04020000Z0ED)
R45  value 270  [0603L]  (hidden comment: CRCW0603270RJNEA)
R47  value 2.32k  [0603L]  (hidden comment: RC0603FR-072K32L)
R48  value 0  [0402L]  (hidden comment: CRCW04020000Z0ED)
R50  Used in BOM report  [0402L]  (value not drawn)
R51  value 51  [0402L]  (hidden comment: CRCW040251R0JNED)
R56  value 270  [0603L]  (hidden comment: CRCW0603270RJNEA)
R59  value 0  [0402L]  (hidden comment: CRCW04020000Z0ED)
R60  value 0  [0402L]  (hidden comment: CRCW04020000Z0ED)
R61  value 0  [0402L]  (hidden comment: CRCW04020000Z0ED)
R62  value 0  [0402L]  (hidden comment: CRCW04020000Z0ED)
R63  value 0  [0402L]  (hidden comment: CRCW04020000Z0ED)
R64  value 0  [0402L]  (hidden comment: CRCW04020000Z0ED)
R122  value 1.3k  [0603L]  (hidden comment: RC0603JR-071K3L)
R142  value 0  [0603L]  (hidden comment: ERJ-3GEY0R00V)
R143  value 0  [0603L]  (hidden comment: ERJ-3GEY0R00V)
R160  value 0  [0402L]  (hidden comment: CRCW04020000Z0ED)
R161  value 0  [0402L]  (hidden comment: CRCW04020000Z0ED)
R166  ValueDisplayed: 560  [0402L]  (hidden comment: CRCW0402560RJNED)
R167  ValueDisplayed: 560  [0402L]  (hidden comment: CRCW0402560RJNED)
Status1  value Green  [LED_LTST-C190]  (hidden comment: LTST-C190GKT)
Status2  value Green  [LED_LTST-C190]  (hidden comment: LTST-C190GKT)
U6  LMK04828BISQ/NOPB  [NKD0064A]

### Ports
ADC_DEVCLK+ (out), ADC_DEVCLK- (out), ADC_SYSREF+ (out), ADC_SYSREF- (out), DEVCLK (in), DEVCLKARX_N (out), DEVCLKARX_P (out), DEVCLKBRX_N (out), DEVCLKBRX_P (out), LMK04828_CSb (in), LMK04828_RESET (in), LMK04828_SYNC (in), LMK_TRF_CLK (in), LMK_TRF_DATA (bidir), SYNC_SE (in), SYSREFRX_N (out), SYSREFRX_P (out), TRF_OutA+ (in), TRF_OutA- (in)

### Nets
GND: C85.1 C88.2 C102.2 C103.2 C104.2 C105.2 C106.2 C107.2 C108.2 C109.2 C110.2 C111.2 C114.1 C120.2 C121.2 C122.2 C124.2 C206.2 C207.2 C208.2 C209.2 LF2.2 LF3.1 LMKCLK.2 LMKCLK.3 LMKCLK.4 LMKCLK.5 R45.1 R50.2 R51.1 R56.1 R122.1 U6.65(PAD)
Vcc2: C103.1 L2.2 U6.17(Vcc2_CG1)
Vcc3: C106.1 L4.2 U6.21(Vcc3_SYSREF)
Vcc4: C111.1 L19.2 U6.26(Vcc4_CG2)
Vcc6: C105.1 L3.2 U6.36(Vcc6_PLL1)
Vcc9: C110.1 L5.2 U6.45(Vcc9_CP2)
Vcc11: C120.1 L21.2 U6.53(Vcc11_CG3)
Vcc12: C121.1 L22.2 U6.64(Vcc12_CG0)
VIO_3P3V_LMK_CLK: L2.1 L4.1 L19.1 L21.1 L22.1 R47.2
VIO_3P3V_LMK_PLL: C102.1 C104.1 C107.1 C108.1 C109.1 C206.1 C207.1 C208.1 C209.1 L3.1 L5.1 U6.10(Vcc1_VCO) U6.33(Vcc5_DIG) U6.39(Vcc7_OSCout) U6.42(Vcc8_OSCin) U6.47(Vcc10_PLL2)
CLK0_N: R63.1 U6.2(DCLKout0*)
CLK0_P: R64.1 U6.1(DCLKout0)
CLK3_N: R61.1 U6.14(SDCLKout3*)
CLK3_P: R62.1 U6.13(SDCLKout3)
CLK4_N: R59.1 U6.25(DCLKout4*)
CLK4_P: R60.1 U6.24(DCLKout4)
CLK10_N: R160.1 R167.2 U6.55(DCLKout10*)
CLK10_P: R161.1 R167.1 U6.54(DCLKout10)
CLK11_N: R43.1 R166.2 U6.57(SDCLKout11*)
CLK11_P: R44.1 R166.1 U6.56(SDCLKout11)
CLKin1_N: C112.1 C123.1 U6.35(CLKin1*/Fin*/FBCLKin*)
CLKin1_P: C113.1 C114.2 U6.34(CLKin1/Fin/FBCLKin)
DEV_CLK_N: R160.2 ; port ADC_DEVCLK-
DEV_CLK_P: R161.2 ; port ADC_DEVCLK+
DEVCLKARX_N: R60.2 ; port DEVCLKARX_N
DEVCLKARX_P: R59.2 ; port DEVCLKARX_P
DEVCLKBRX_N: R63.2 ; port DEVCLKBRX_N
DEVCLKBRX_P: R64.2 ; port DEVCLKBRX_P
LMK04828_CSb: U6.18(CS*) ; port LMK04828_CSb
LMK04828_RESET: R122.2 U6.5(RESET) ; port LMK04828_RESET
LMK04828_SYNC: R142.1 ; port LMK04828_SYNC
LMK_TRF_CLK: U6.19(SCK) ; port LMK_TRF_CLK
LMK_TRF_DATA: U6.20(SDIO) ; port LMK_TRF_DATA
SYNC_SE: R143.1 ; port SYNC_SE
SYSREFRX_N: R61.2 ; port SYSREFRX_N
SYSREFRX_P: R62.2 ; port SYSREFRX_P
SYSREFTX_N: R43.2 ; port ADC_SYSREF-
SYSREFTX_P: R44.2 ; port ADC_SYSREF+
TRF_OutA_N: C112.2 ; port TRF_OutA-
TRF_OutA_P: C113.2 ; port TRF_OutA+
U6-3: U6.3(SDCLKout1)
U6-4: U6.4(SDCLKout1*)
U6-7: U6.7(NC)
U6-8: U6.8(NC)
U6-9: U6.9(NC)
U6-15: U6.15(DCLKout2)
U6-16: U6.16(DCLKout2*)
U6-22: U6.22(SDCLKout5)
U6-23: U6.23(SDCLKout5*)
U6-27: U6.27(DCLKout6)
U6-28: U6.28(DCLKout6*)
U6-29: U6.29(SDCLKout7)
U6-30: U6.30(SDCLKout7*)
U6-32: U6.32(CPout1)
U6-40: U6.40(OSCout/CLKin2)
U6-41: U6.41(OSCout*/CLKin2*)
U6-49: U6.49(SDCLKout9)
U6-50: U6.50(SDCLKout9*)
U6-51: U6.51(DCLKout8)
U6-52: U6.52(DCLKout8*)
U6-58: U6.58(CLKin_SEL0)
U6-59: U6.59(CLKin_SEL1)
U6-60: U6.60(SDCLKout13)
U6-61: U6.61(SDCLKout13*)
U6-62: U6.62(DCLKout12)
U6-63: U6.63(DCLKout12*)
NetC85_2: C85.2 U6.43(OSCin)
NetC86_1: C86.1 C123.2 R48.1 R50.1
NetC86_2: C86.2 U6.44(OSCin*)
NetC87_1: C87.1 U6.38(CLKin0*)
NetC87_2: C87.2 ; port DEVCLK
NetC88_1: C88.1 U6.37(CLKin0)
NetC122_1: C122.1 U6.11(LDObyp1)
NetC124_1: C124.1 U6.12(LDObyp2)
NetLD1_1: LD1.1 Status1.1(A) U6.31(Status_LD1)
NetLD2_1: LD2.1 Status2.1(A) U6.48(Status_LD2)
NetLF1_1: LF1.1 LF2.1 U6.46(CPout2)
NetLF1_2: LF1.2 LF3.2
NetLMKCLK_1: LMKCLK.1 R48.2 R51.2
NetR45_2: R45.2 Status2.2(K)
NetR47_1: R47.1 R142.2 R143.2 U6.6(SYNC)
NetR56_2: R56.2 Status1.2(K)

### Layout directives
differential pair: CLK0_N, CLK0_P, CLK3_N, CLK3_P, CLK4_N, CLK4_P, CLK10_N, CLK10_P, CLK11_N, CLK11_P, CLKin1_N, CLKin1_P, DEV_CLK_N, DEV_CLK_P, DEVCLKARX_N, DEVCLKARX_P, DEVCLKBRX_N, DEVCLKBRX_P, SYSREFRX_N, SYSREFRX_P, SYSREFTX_N, SYSREFTX_P

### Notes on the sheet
- As illustrated on the schematic, add short stub traces extending out from package to aid solderability.
- (near C113) Let C123 and C112 share a pad on the common net. Let C114 and C113 share a pad on the common net.
- Polarity inversion on these 2 signals

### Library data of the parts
C85-C88 C103-C107 C109-C114 C120 C121 C123 C124 C206-C209 = C1005X5R1A104K: as C73 on sheet ADC12JXXXXEVM_A_3_TRF3765
C102 = C1005X7R1C103K: CAP, CERM, 0.01uF, 16V, +/-10%, X7R, 0402; Manufacturer: TDK; Polarized: N; CompType: Capacitor; U/M: EA; Cap_F: 0.00000001; Tolerance_%: 10; ESR_Ohm: 0.0623; Value1: 0.0623 ohm; VDC_V: 16; TaMin_C: -55; TaMax_C: 125; Cap_Case: 0402
C108 = C1608X5R1C105K: CAP, CERM, 1uF, 16V, +/-10%, X5R, 0603; Manufacturer: TDK; Polarized: N; CompType: Capacitor; U/M: EA; Cap_F: 0.000001; Tolerance_%: 10; ESR_Ohm: 0.0057; Value1: 0.0057 ohm; VDC_V: 16; TaMin_C: -55; TaMax_C: 85; Cap_Case: 0603
C122 = C0805C106K8PACTU: CAP, CERM, 10uF, 10V, +/-10%, X5R, 0805; Manufacturer: Kemet; Cap_Case: 0805; ESR_Ohm: 0.003; IRMS_A: 11.43; Polarized: N; TaMax_C: 85; TaMin_C: -55; Tolerance_%: 10; Cap_F: 10.0E-6; CompType: Capacitor; Value1: 0.003 ohm
L2-L5 L19 L21 L22 = BLM18SG331TN1D: 1.5A Ferrite Bead, 330 ohm @ 100MHz, SMD; Manufacturer: MuRata; Imax_A: 1.5; DCR_ohm: 0.07; Value1: 0.07 ohm; ZTyp@100MHz_Ohm: 330; U/M: EA
LD1 LD2 = TESTPOINT: TEST POINT.  No entry in BOM.
LF1 = C1608C0G1E392J: CAP, CERM, 3900pF, 25V, +/-5%, C0G/NP0, 0603; Manufacturer: TDK; Polarized: N; CompType: Capacitor; U/M: EA; Cap_F: 0.0000000039; Tolerance_%: 5; VDC_V: 25; TaMin_C: -55; TaMax_C: 125; Cap_Case: 0603
LF2 = 06035A470JAT2A: CAP, CERM, 47pF, 50V, +/-5%, C0G/NP0, 0603; Manufacturer: AVX; Polarized: N; CompType: Capacitor; U/M: EA; Cap_F: 0.000000000047; Tolerance_%: 5; ESR_Ohm: 0.174; Value1: 0.174 ohm; VDC_V: 50; TaMin_C: -55; TaMax_C: 125; Cap_Case: 0603
LF3 = RC0603FR-07619RL: RES, 619 ohm, 1%, 0.1W, 0603; Manufacturer: Yageo America; Alternate Manufacturer: Any; Alternate PartNumber: Equivalent; CompType: Resistor; Value_Code: 619R; Tolerance_%: 1; Power_W: 0.1; VDC_V: 150; TempCo: 200 ppm/C; EIA_Code: E96; U/M: EA
LMKCLK = SASF546-P26-X1: as EXT_VCO on sheet ADC12JXXXXEVM_A_3_TRF3765
R43 R44 R59-R64 R160 R161 = CRCW04020000Z0ED: RES, 0 ohm, 5%, 0.063W, 0402; Manufacturer: Vishay-Dale; CompType: Resistor; Value_Code: 0000; Tolerance_%: 5; Power_W: 0.063; VDC_V: 50; TempCo: 200 ppm/C; EIA_Code: E24; U/M: EA
R45 R56 = CRCW0603270RJNEA: RES, 270 ohm, 5%, 0.1W, 0603; Manufacturer: Vishay-Dale; Alternate Manufacturer: Any; Alternate PartNumber: Equivalent; CompType: Resistor; Value_Code: 270R; Tolerance_%: 5; Power_W: 0.1; VDC_V: 75; TempCo: 200 ppm/C; EIA_Code: E24; U/M: EA
R47 = RC0603FR-072K32L: RES, 2.32k ohm, 1%, 0.1W, 0603; Manufacturer: Yageo America; CompType: Resistor; Res_ohm: 2320; Value_Code: 2k32; Tolerance_%: 1; Power_W: 0.1; VDC_V: 150; TempCo: 200 ppm/C; EIA_Code: E96; U/M: EA
R48 = CRCW04020000Z0ED: RES, 0 ohm, 5%, 0.063W, 0402; Manufacturer: Vishay-Dale; Alternate Manufacturer: Any; Alternate PartNumber: Equivalent; CompType: Resistor; Value_Code: 0000; Tolerance_%: 5; Power_W: 0.063; VDC_V: 50; TempCo: 200 ppm/C; EIA_Code: E24; U/M: EA
R50 = Resistor: RES, xxx ohm, x%, xW, [PackageReference]; U/M: EA
R51 = CRCW040251R0JNED: RES, 51 ohm, 5%, 0.063W, 0402; Manufacturer: Vishay-Dale; Alternate Manufacturer: Any; Alternate PartNumber: Equivalent; CompType: Resistor; Value_Code: 51R0; Tolerance_%: 5; Power_W: 0.063; VDC_V: 50; TempCo: 200 ppm/C; EIA_Code: E24; U/M: EA
R122 = RC0603JR-071K3L: RES, 1.3k ohm, 5%, 0.1W, 0603; Manufacturer: Yageo America; CompType: Resistor; Res_ohm: 1300; Value_Code: 1k30; Tolerance_%: 5; Power_W: 0.1; VDC_V: 50; TempCo: 100 ppm/C; EIA_Code: E24; U/M: EA
R142 R143 = ERJ-3GEY0R00V: RES, 0 ohm, 5%, 0.1W, 0603; Manufacturer: Panasonic; CompType: Resistor; Value_Code: 0000; Tolerance_%: 5; Power_W: 0.1; VDC_V: 50; TempCo: 600 ppm/C; EIA_Code: E24; U/M: EA
R166 R167 = CRCW0402560RJNED: RES, 560, 5%, 0.063 W, 0402; Manufacturer: Vishay-Dale; CompType: Resistor; Value: 560; Value_Code: 560R; Tolerance_%: 5; Power_W: 0.063; Value2: 0.063W; VDC_V: 50; TempCo: 200 ppm/C; EIA_Code: E24; U/M: EA
Status1 Status2 = LTST-C190GKT: as LD on sheet ADC12JXXXXEVM_A_3_TRF3765
U6 = LMK04828BISQ/NOPB: Low-Noise Clock Jitter Cleaner with Dual Loop PLLs, NKD0064A; Alternate Manufacturer: None; Manufacturer: Texas Instruments; SymbolCreator: a0411947/a0412235; CompType: IC; U/M: EA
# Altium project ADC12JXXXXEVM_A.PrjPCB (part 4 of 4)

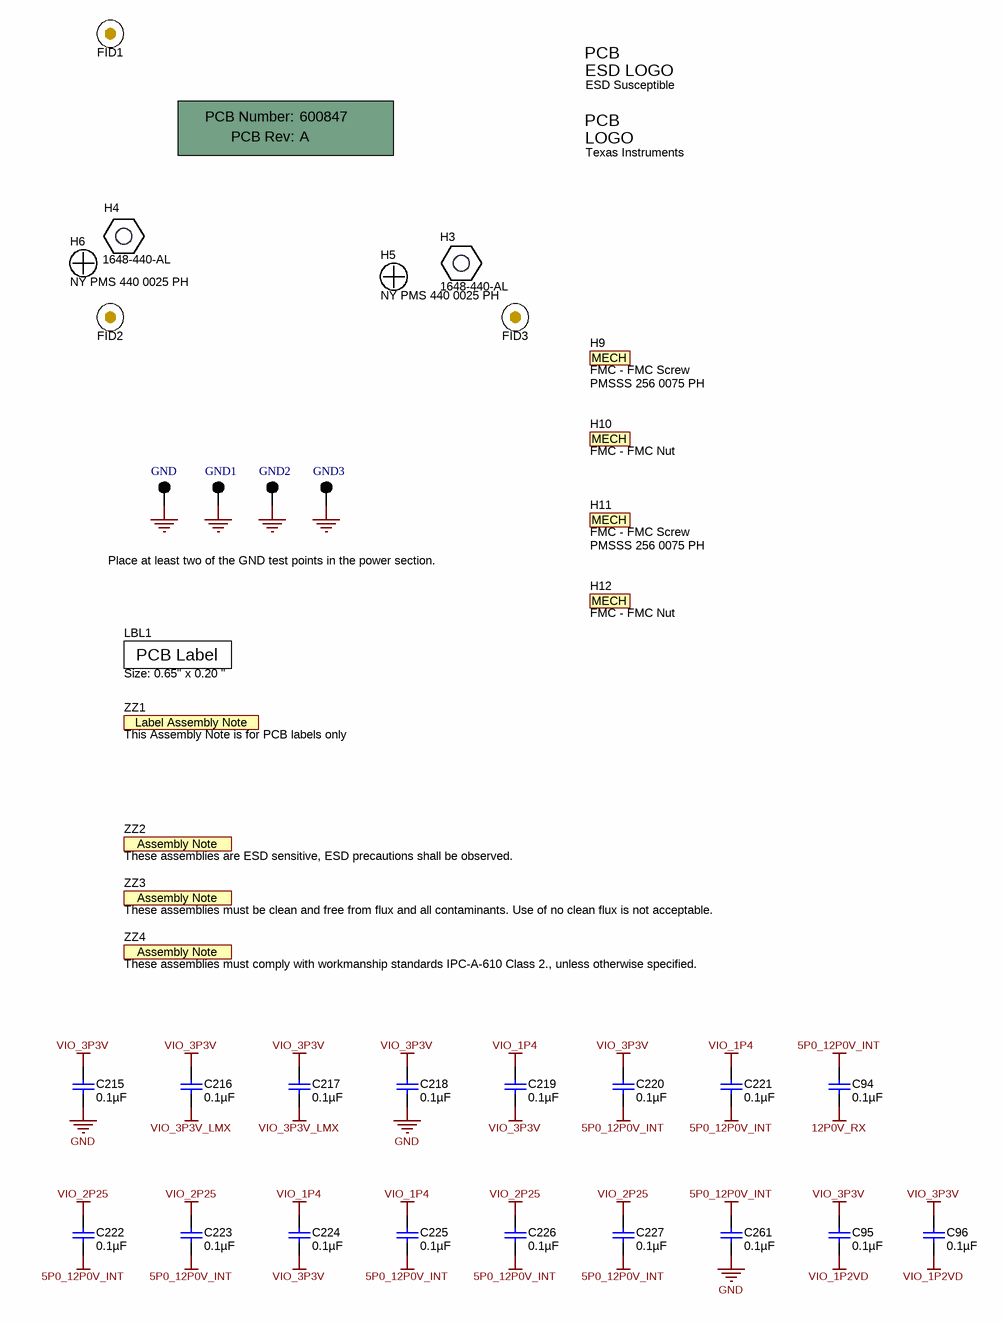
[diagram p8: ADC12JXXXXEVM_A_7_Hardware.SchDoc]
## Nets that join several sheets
5P0_12P0V_INT: ADC12JXXXXEVM_A_5_Power (16 pins), ADC12JXXXXEVM_A_7_Hardware (9 pins)
12P0V_RX: ADC12JXXXXEVM_A_2_FMC (FMC_RX1.C35 FMC_RX1.C37), ADC12JXXXXEVM_A_5_Power (EXT5V_FMC12V.3), ADC12JXXXXEVM_A_7_Hardware (C94.2)
GND: ADC12JXXXXEVM_A_1_ADC_IO (102 pins), ADC12JXXXXEVM_A_2_FMC (164 pins), ADC12JXXXXEVM_A_3_TRF3765 (64 pins), ADC12JXXXXEVM_A_4_LMK04828 (33 pins), ADC12JXXXXEVM_A_5_Power (80 pins), ADC12JXXXXEVM_A_6_InterfaceControl (20 pins), ADC12JXXXXEVM_A_7_Hardware (7 pins)
VIO_1P2VA: ADC12JXXXXEVM_A_1_ADC_IO (18 pins), ADC12JXXXXEVM_A_5_Power (C177.1 C188.1 L15.2)
VIO_1P2VD: ADC12JXXXXEVM_A_1_ADC_IO (28 pins), ADC12JXXXXEVM_A_5_Power (C189.1 C197.1 L16.2), ADC12JXXXXEVM_A_7_Hardware (C95.2 C96.2)
VIO_1P4: ADC12JXXXXEVM_A_5_Power (5 pins), ADC12JXXXXEVM_A_7_Hardware (C219.1 C221.1 C224.1 C225.1)
VIO_1P9V: ADC12JXXXXEVM_A_1_ADC_IO (20 pins), ADC12JXXXXEVM_A_5_Power (6 pins), ADC12JXXXXEVM_A_6_InterfaceControl (C130.1 R123.2 U12.15)
VIO_2P25: ADC12JXXXXEVM_A_5_Power (5 pins), ADC12JXXXXEVM_A_7_Hardware (C222.1 C223.1 C226.1 C227.1)
VIO_3P3V: ADC12JXXXXEVM_A_1_ADC_IO (15 pins), ADC12JXXXXEVM_A_5_Power (C153.1 C163.1 L9.2), ADC12JXXXXEVM_A_6_InterfaceControl (FTDI_3P3V.1 J3.2), ADC12JXXXXEVM_A_7_Hardware (9 pins)
VIO_3P3V_LMK_CLK: ADC12JXXXXEVM_A_4_LMK04828 (6 pins), ADC12JXXXXEVM_A_5_Power (C116.1 C171.1 L13.2), ADC12JXXXXEVM_A_6_InterfaceControl (R131.1)
VIO_3P3V_LMK_PLL: ADC12JXXXXEVM_A_4_LMK04828 (16 pins), ADC12JXXXXEVM_A_5_Power (C164.1 C165.1 L10.2)
VIO_3P3V_LMX: ADC12JXXXXEVM_A_3_TRF3765 (19 pins), ADC12JXXXXEVM_A_5_Power (C144.1 C152.1 L6.2), ADC12JXXXXEVM_A_6_InterfaceControl (R130.1), ADC12JXXXXEVM_A_7_Hardware (C216.2 C217.2)
ADC_OR_T0: ADC12JXXXXEVM_A_1_ADC_IO (D2.2 OR.3 U2.25), ADC12JXXXXEVM_A_2_FMC (FMC_RX1.G27)
ADC_OR_T1: ADC12JXXXXEVM_A_1_ADC_IO (D4.2 OR.1 U2.26), ADC12JXXXXEVM_A_2_FMC (FMC_RX1.D26)
D0_N: ADC12JXXXXEVM_A_1_ADC_IO (C9.1), ADC12JXXXXEVM_A_2_FMC (FMC_RX1.C6)
D0_P: ADC12JXXXXEVM_A_1_ADC_IO (C7.1), ADC12JXXXXEVM_A_2_FMC (FMC_RX1.C7)
D1_N: ADC12JXXXXEVM_A_1_ADC_IO (C12.1), ADC12JXXXXEVM_A_2_FMC (FMC_RX1.A2)
D1_P: ADC12JXXXXEVM_A_1_ADC_IO (C10.1), ADC12JXXXXEVM_A_2_FMC (FMC_RX1.A3)
D2_N: ADC12JXXXXEVM_A_1_ADC_IO (C14.1), ADC12JXXXXEVM_A_2_FMC (FMC_RX1.A6)
D2_P: ADC12JXXXXEVM_A_1_ADC_IO (C13.1), ADC12JXXXXEVM_A_2_FMC (FMC_RX1.A7)
D3_N: ADC12JXXXXEVM_A_1_ADC_IO (C17.1), ADC12JXXXXEVM_A_2_FMC (FMC_RX1.A10)
D3_P: ADC12JXXXXEVM_A_1_ADC_IO (C15.1), ADC12JXXXXEVM_A_2_FMC (FMC_RX1.A11)
D4_N: ADC12JXXXXEVM_A_1_ADC_IO (C21.1), ADC12JXXXXEVM_A_2_FMC (FMC_RX1.A14)
D4_P: ADC12JXXXXEVM_A_1_ADC_IO (C20.1), ADC12JXXXXEVM_A_2_FMC (FMC_RX1.A15)
D5_N: ADC12JXXXXEVM_A_1_ADC_IO (C23.1), ADC12JXXXXEVM_A_2_FMC (FMC_RX1.A18)
D5_P: ADC12JXXXXEVM_A_1_ADC_IO (C22.1), ADC12JXXXXEVM_A_2_FMC (FMC_RX1.A19)
D6_N: ADC12JXXXXEVM_A_1_ADC_IO (C28.1), ADC12JXXXXEVM_A_2_FMC (FMC_RX1.B16)
D6_P: ADC12JXXXXEVM_A_1_ADC_IO (C26.1), ADC12JXXXXEVM_A_2_FMC (FMC_RX1.B17)
D7_N: ADC12JXXXXEVM_A_1_ADC_IO (C31.1), ADC12JXXXXEVM_A_2_FMC (FMC_RX1.B12)
D7_P: ADC12JXXXXEVM_A_1_ADC_IO (C29.1), ADC12JXXXXEVM_A_2_FMC (FMC_RX1.B13)
DEV_CLK_N: ADC12JXXXXEVM_A_1_ADC_IO (C263.2), ADC12JXXXXEVM_A_4_LMK04828 (R160.2)
DEV_CLK_P: ADC12JXXXXEVM_A_1_ADC_IO (C262.2), ADC12JXXXXEVM_A_4_LMK04828 (R161.2)
DEVCLKARX_N: ADC12JXXXXEVM_A_2_FMC (FMC_RX1.D5), ADC12JXXXXEVM_A_4_LMK04828 (R60.2)
DEVCLKARX_P: ADC12JXXXXEVM_A_2_FMC (FMC_RX1.D4), ADC12JXXXXEVM_A_4_LMK04828 (R59.2)
DEVCLKBRX_N: ADC12JXXXXEVM_A_2_FMC (FMC_RX1.G7), ADC12JXXXXEVM_A_4_LMK04828 (R63.2)
DEVCLKBRX_P: ADC12JXXXXEVM_A_2_FMC (FMC_RX1.G6), ADC12JXXXXEVM_A_4_LMK04828 (R64.2)
FMC_DEVCLK_N: ADC12JXXXXEVM_A_1_ADC_IO (C93.2), ADC12JXXXXEVM_A_2_FMC (FMC_RX1.K29)
FMC_DEVCLK_P: ADC12JXXXXEVM_A_1_ADC_IO (C92.2), ADC12JXXXXEVM_A_2_FMC (FMC_RX1.K28)
FMC_SYSREF_N: ADC12JXXXXEVM_A_1_ADC_IO (C91.2), ADC12JXXXXEVM_A_2_FMC (FMC_RX1.K38)
FMC_SYSREF_P: ADC12JXXXXEVM_A_1_ADC_IO (C90.2), ADC12JXXXXEVM_A_2_FMC (FMC_RX1.K37)
FTDI_TRF_R1: ADC12JXXXXEVM_A_3_TRF3765 (U4.6), ADC12JXXXXEVM_A_6_InterfaceControl (U13.43)
LMK04828_CSb: ADC12JXXXXEVM_A_4_LMK04828 (U6.18), ADC12JXXXXEVM_A_6_InterfaceControl (R68.1 R69.1 R98.1 R104.2)
LMK04828_RESET: ADC12JXXXXEVM_A_2_FMC (FMC_RX1.J16), ADC12JXXXXEVM_A_4_LMK04828 (R122.2 U6.5)
LMK04828_SYNC: ADC12JXXXXEVM_A_2_FMC (FMC_RX1.J15), ADC12JXXXXEVM_A_4_LMK04828 (R142.1)
LMK_TRF_CLK: ADC12JXXXXEVM_A_3_TRF3765 (U4.4), ADC12JXXXXEVM_A_4_LMK04828 (U6.19), ADC12JXXXXEVM_A_6_InterfaceControl (R102.1 R115.1 R121.1 R129.2)
LMK_TRF_DATA: ADC12JXXXXEVM_A_3_TRF3765 (U4.3), ADC12JXXXXEVM_A_4_LMK04828 (U6.20), ADC12JXXXXEVM_A_6_InterfaceControl (R101.1 R114.1 R120.1 R128.2)
NetC87_2: ADC12JXXXXEVM_A_1_ADC_IO (C89.1 DEVCLK.1 R165.2), ADC12JXXXXEVM_A_4_LMK04828 (C87.2)
NetFMC_RX1_C30: ADC12JXXXXEVM_A_2_FMC (FMC_RX1.C30 J1.2 U16.6), ADC12JXXXXEVM_A_6_InterfaceControl (R127.2)
NetFMC_RX1_C31: ADC12JXXXXEVM_A_2_FMC (FMC_RX1.C31 J1.1 U16.5), ADC12JXXXXEVM_A_6_InterfaceControl (R126.2)
NetFMC_RX1_E12: ADC12JXXXXEVM_A_1_ADC_IO (R136.2), ADC12JXXXXEVM_A_2_FMC (FMC_RX1.E12)
NetFMC_RX1_E13: ADC12JXXXXEVM_A_1_ADC_IO (R137.2), ADC12JXXXXEVM_A_2_FMC (FMC_RX1.E13)
NetFMC_RX1_E36: ADC12JXXXXEVM_A_1_ADC_IO (R138.2), ADC12JXXXXEVM_A_2_FMC (FMC_RX1.E36)
NetFMC_RX1_G30: ADC12JXXXXEVM_A_2_FMC (FMC_RX1.G30), ADC12JXXXXEVM_A_6_InterfaceControl (R121.2)
NetFMC_RX1_G33: ADC12JXXXXEVM_A_2_FMC (FMC_RX1.G33), ADC12JXXXXEVM_A_6_InterfaceControl (R69.2)
NetFMC_RX1_G34: ADC12JXXXXEVM_A_2_FMC (FMC_RX1.G34), ADC12JXXXXEVM_A_6_InterfaceControl (R119.2)
NetFMC_RX1_G36: ADC12JXXXXEVM_A_2_FMC (FMC_RX1.G36), ADC12JXXXXEVM_A_6_InterfaceControl (R57.2)
NetFMC_RX1_G37: ADC12JXXXXEVM_A_2_FMC (FMC_RX1.G37), ADC12JXXXXEVM_A_6_InterfaceControl (R55.2)
NetFMC_RX1_H34: ADC12JXXXXEVM_A_2_FMC (FMC_RX1.H34), ADC12JXXXXEVM_A_6_InterfaceControl (R120.2)
NetFMC_RX1_H37: ADC12JXXXXEVM_A_2_FMC (FMC_RX1.H37), ADC12JXXXXEVM_A_6_InterfaceControl (R58.2)
NetFMC_RX1_H38: ADC12JXXXXEVM_A_2_FMC (FMC_RX1.H38), ADC12JXXXXEVM_A_6_InterfaceControl (R54.2)
NetR31_1: ADC12JXXXXEVM_A_1_ADC_IO (R31.1 U3.12), ADC12JXXXXEVM_A_6_InterfaceControl (R117.1 R124.1 R126.1)
NetR32_1: ADC12JXXXXEVM_A_1_ADC_IO (R32.1 U3.13), ADC12JXXXXEVM_A_6_InterfaceControl (R125.1 R127.1)
NetR54_1: ADC12JXXXXEVM_A_1_ADC_IO (U2.59), ADC12JXXXXEVM_A_6_InterfaceControl (R54.1 R118.1 R139.2 SPI.2)
NetR55_1: ADC12JXXXXEVM_A_1_ADC_IO (U2.56), ADC12JXXXXEVM_A_6_InterfaceControl (R55.1 R110.1 SPI.4)
NetR57_1: ADC12JXXXXEVM_A_1_ADC_IO (U2.57), ADC12JXXXXEVM_A_6_InterfaceControl (R57.1 R111.1 R140.2 SPI.6)
NetR58_1: ADC12JXXXXEVM_A_1_ADC_IO (U2.58), ADC12JXXXXEVM_A_6_InterfaceControl (R58.1 R109.1 R141.2 SPI.8)
SYNC_N: ADC12JXXXXEVM_A_1_ADC_IO (R20.2), ADC12JXXXXEVM_A_2_FMC (FMC_RX1.G13)
SYNC_P: ADC12JXXXXEVM_A_1_ADC_IO (R19.2), ADC12JXXXXEVM_A_2_FMC (FMC_RX1.G12)
SYNC_SE: ADC12JXXXXEVM_A_1_ADC_IO (R134.1), ADC12JXXXXEVM_A_2_FMC (FMC_RX1.H31), ADC12JXXXXEVM_A_4_LMK04828 (R143.1)
SYSREFRX_N: ADC12JXXXXEVM_A_2_FMC (FMC_RX1.G10), ADC12JXXXXEVM_A_4_LMK04828 (R61.2)
SYSREFRX_P: ADC12JXXXXEVM_A_2_FMC (FMC_RX1.G9), ADC12JXXXXEVM_A_4_LMK04828 (R62.2)
SYSREFTX_N: ADC12JXXXXEVM_A_1_ADC_IO (C37.2), ADC12JXXXXEVM_A_4_LMK04828 (R43.2)
SYSREFTX_P: ADC12JXXXXEVM_A_1_ADC_IO (C35.2), ADC12JXXXXEVM_A_4_LMK04828 (R44.2)
TRF3765_STROBE: ADC12JXXXXEVM_A_3_TRF3765 (U4.5), ADC12JXXXXEVM_A_6_InterfaceControl (R97.1 R113.1 R116.2 R119.1)
TRF_OutA_N: ADC12JXXXXEVM_A_3_TRF3765 (R157.1 R159.2 U17.6), ADC12JXXXXEVM_A_4_LMK04828 (C112.2)
TRF_OutA_P: ADC12JXXXXEVM_A_3_TRF3765 (R156.1 R158.2 U17.7), ADC12JXXXXEVM_A_4_LMK04828 (C113.2)
TRF_OutB_N: ADC12JXXXXEVM_A_1_ADC_IO (C33.2), ADC12JXXXXEVM_A_3_TRF3765 (C83.2 R36.2)
TRF_OutB_P: ADC12JXXXXEVM_A_1_ADC_IO (C32.2), ADC12JXXXXEVM_A_3_TRF3765 (C75.2 R29.2)

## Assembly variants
002_ADC12J4000EVM: not fitted C1 C6 C30 C36 C85 C86 C87 C90 C91 C92 C93 C114 C123 C230 C231 C234 C235 C247 C250 C251 C262 C263 FID1 FID2 FID3 R7 R8 R9 R18 R21 R22 R23 R24 R26 R29 R30 R36 R40 R42 R50 R54 R55 R57 R58 R69 R73 R75 R83 R84 R90 R92 R95 R104 R116 R119 R120 R121 R126 R127 R128 R129 R139 R140 R141 R142 R146 R151 R153 R165 U16
001_LM15851EVM: not fitted C1 C6 C30 C36 C85 C86 C87 C90 C91 C92 C93 C114 C123 C230 C231 C234 C235 C247 C250 C251 C262 C263 FID1 FID2 FID3 R18 R21 R22 R23 R24 R26 R29 R30 R36 R40 R42 R50 R54 R55 R57 R58 R69 R73 R75 R83 R84 R90 R92 R95 R104 R116 R119 R120 R121 R126 R127 R128 R129 R139 R140 R141 R142 R146 R151 R153 R165 U16
003_ADC12J2700EVM: not fitted C1 C6 C30 C36 C85 C86 C87 C90 C91 C92 C93 C114 C123 C230 C231 C234 C235 C247 C250 C251 C262 C263 FID1 FID2 FID3 R7 R8 R9 R18 R21 R22 R23 R24 R26 R29 R30 R36 R40 R42 R50 R54 R55 R57 R58 R69 R73 R75 R83 R84 R90 R92 R95 R104 R116 R119 R120 R121 R126 R127 R128 R129 R139 R140 R141 R142 R146 R151 R153 R165 U16
004_ADC12J1600EVM: not fitted C1 C6 C30 C36 C85 C86 C87 C90 C91 C92 C93 C114 C123 C230 C231 C234 C235 C247 C250 C251 C262 C263 FID1 FID2 FID3 R7 R8 R9 R18 R21 R22 R23 R24 R26 R29 R30 R36 R40 R42 R50 R54 R55 R57 R58 R69 R73 R75 R83 R84 R90 R92 R95 R104 R116 R119 R120 R121 R126 R127 R128 R129 R139 R140 R141 R142 R146 R151 R153 R165 U16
